VERSION 5.7 ;
  NOWIREEXTENSIONATPIN ON ;
  DIVIDERCHAR "/" ;
  BUSBITCHARS "[]" ;
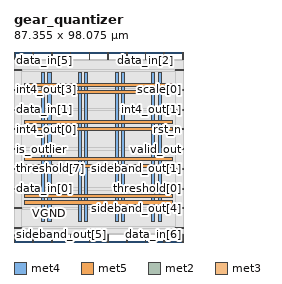
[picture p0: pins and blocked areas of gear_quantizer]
MACRO gear_quantizer
  CLASS BLOCK ;
  FOREIGN gear_quantizer ;
  ORIGIN 0.000 0.000 ;
  SIZE 87.355 BY 98.075 ;
  PIN VGND
    DIRECTION INOUT ;
    USE GROUND ;
    PORT
      LAYER met4 ;
        RECT 17.505 10.640 19.105 87.280 ;
    END
    PORT
      LAYER met4 ;
        RECT 36.480 10.640 38.080 87.280 ;
    END
    PORT
      LAYER met4 ;
        RECT 55.455 10.640 57.055 87.280 ;
    END
    PORT
      LAYER met4 ;
        RECT 74.430 10.640 76.030 87.280 ;
    END
    PORT
      LAYER met5 ;
        RECT 5.280 22.900 81.660 24.500 ;
    END
    PORT
      LAYER met5 ;
        RECT 5.280 41.940 81.660 43.540 ;
    END
    PORT
      LAYER met5 ;
        RECT 5.280 60.980 81.660 62.580 ;
    END
    PORT
      LAYER met5 ;
        RECT 5.280 80.020 81.660 81.620 ;
    END
  END VGND
  PIN VPWR
    DIRECTION INOUT ;
    USE POWER ;
    PORT
      LAYER met4 ;
        RECT 14.205 10.640 15.805 87.280 ;
    END
    PORT
      LAYER met4 ;
        RECT 33.180 10.640 34.780 87.280 ;
    END
    PORT
      LAYER met4 ;
        RECT 52.155 10.640 53.755 87.280 ;
    END
    PORT
      LAYER met4 ;
        RECT 71.130 10.640 72.730 87.280 ;
    END
    PORT
      LAYER met5 ;
        RECT 5.280 19.600 81.660 21.200 ;
    END
    PORT
      LAYER met5 ;
        RECT 5.280 38.640 81.660 40.240 ;
    END
    PORT
      LAYER met5 ;
        RECT 5.280 57.680 81.660 59.280 ;
    END
    PORT
      LAYER met5 ;
        RECT 5.280 76.720 81.660 78.320 ;
    END
  END VPWR
  PIN clk
    DIRECTION INPUT ;
    USE SIGNAL ;
    ANTENNAGATEAREA 0.852000 ;
    PORT
      LAYER met2 ;
        RECT 48.390 0.000 48.670 4.000 ;
    END
  END clk
  PIN data_in[0]
    DIRECTION INPUT ;
    USE SIGNAL ;
    ANTENNAGATEAREA 0.213000 ;
    PORT
      LAYER met3 ;
        RECT 0.000 27.240 4.000 27.840 ;
    END
  END data_in[0]
  PIN data_in[1]
    DIRECTION INPUT ;
    USE SIGNAL ;
    ANTENNAGATEAREA 0.196500 ;
    PORT
      LAYER met3 ;
        RECT 0.000 68.040 4.000 68.640 ;
    END
  END data_in[1]
  PIN data_in[2]
    DIRECTION INPUT ;
    USE SIGNAL ;
    ANTENNAGATEAREA 0.196500 ;
    PORT
      LAYER met2 ;
        RECT 67.710 94.075 67.990 98.075 ;
    END
  END data_in[2]
  PIN data_in[3]
    DIRECTION INPUT ;
    USE SIGNAL ;
    ANTENNAGATEAREA 0.213000 ;
    PORT
      LAYER met2 ;
        RECT 48.390 94.075 48.670 98.075 ;
    END
  END data_in[3]
  PIN data_in[4]
    DIRECTION INPUT ;
    USE SIGNAL ;
    ANTENNAGATEAREA 0.213000 ;
    PORT
      LAYER met2 ;
        RECT 58.050 94.075 58.330 98.075 ;
    END
  END data_in[4]
  PIN data_in[5]
    DIRECTION INPUT ;
    USE SIGNAL ;
    ANTENNAGATEAREA 0.159000 ;
    PORT
      LAYER met2 ;
        RECT 9.750 94.075 10.030 98.075 ;
    END
  END data_in[5]
  PIN data_in[6]
    DIRECTION INPUT ;
    USE SIGNAL ;
    ANTENNAGATEAREA 0.213000 ;
    PORT
      LAYER met2 ;
        RECT 87.030 0.000 87.310 4.000 ;
    END
  END data_in[6]
  PIN data_in[7]
    DIRECTION INPUT ;
    USE SIGNAL ;
    ANTENNAGATEAREA 0.213000 ;
    PORT
      LAYER met2 ;
        RECT 77.370 0.000 77.650 4.000 ;
    END
  END data_in[7]
  PIN int4_out[0]
    DIRECTION OUTPUT TRISTATE ;
    USE SIGNAL ;
    ANTENNADIFFAREA 0.795200 ;
    PORT
      LAYER met3 ;
        RECT 0.000 57.840 4.000 58.440 ;
    END
  END int4_out[0]
  PIN int4_out[1]
    DIRECTION OUTPUT TRISTATE ;
    USE SIGNAL ;
    ANTENNADIFFAREA 0.795200 ;
    PORT
      LAYER met3 ;
        RECT 83.355 68.040 87.355 68.640 ;
    END
  END int4_out[1]
  PIN int4_out[2]
    DIRECTION OUTPUT TRISTATE ;
    USE SIGNAL ;
    ANTENNADIFFAREA 0.795200 ;
    PORT
      LAYER met2 ;
        RECT 19.410 94.075 19.690 98.075 ;
    END
  END int4_out[2]
  PIN int4_out[3]
    DIRECTION OUTPUT TRISTATE ;
    USE SIGNAL ;
    ANTENNADIFFAREA 0.795200 ;
    PORT
      LAYER met3 ;
        RECT 0.000 78.240 4.000 78.840 ;
    END
  END int4_out[3]
  PIN is_outlier
    DIRECTION OUTPUT TRISTATE ;
    USE SIGNAL ;
    ANTENNADIFFAREA 0.795200 ;
    PORT
      LAYER met3 ;
        RECT 0.000 47.640 4.000 48.240 ;
    END
  END is_outlier
  PIN round_mode
    DIRECTION INPUT ;
    USE SIGNAL ;
    PORT
      LAYER met3 ;
        RECT 83.355 6.840 87.355 7.440 ;
    END
  END round_mode
  PIN rst_n
    DIRECTION INPUT ;
    USE SIGNAL ;
    ANTENNAGATEAREA 0.213000 ;
    PORT
      LAYER met3 ;
        RECT 83.355 57.840 87.355 58.440 ;
    END
  END rst_n
  PIN scale[0]
    DIRECTION INPUT ;
    USE SIGNAL ;
    ANTENNAGATEAREA 0.213000 ;
    PORT
      LAYER met3 ;
        RECT 83.355 78.240 87.355 78.840 ;
    END
  END scale[0]
  PIN scale[1]
    DIRECTION INPUT ;
    USE SIGNAL ;
    ANTENNAGATEAREA 0.126000 ;
    PORT
      LAYER met2 ;
        RECT 0.090 0.000 0.370 4.000 ;
    END
  END scale[1]
  PIN scale[2]
    DIRECTION INPUT ;
    USE SIGNAL ;
    ANTENNAGATEAREA 0.213000 ;
    PORT
      LAYER met2 ;
        RECT 0.090 94.075 0.370 98.075 ;
    END
  END scale[2]
  PIN scale[3]
    DIRECTION INPUT ;
    USE SIGNAL ;
    ANTENNAGATEAREA 0.213000 ;
    PORT
      LAYER met3 ;
        RECT 0.000 6.840 4.000 7.440 ;
    END
  END scale[3]
  PIN sideband_out[0]
    DIRECTION OUTPUT TRISTATE ;
    USE SIGNAL ;
    ANTENNADIFFAREA 0.795200 ;
    PORT
      LAYER met2 ;
        RECT 29.070 0.000 29.350 4.000 ;
    END
  END sideband_out[0]
  PIN sideband_out[1]
    DIRECTION OUTPUT TRISTATE ;
    USE SIGNAL ;
    ANTENNADIFFAREA 0.445500 ;
    PORT
      LAYER met3 ;
        RECT 83.355 37.440 87.355 38.040 ;
    END
  END sideband_out[1]
  PIN sideband_out[2]
    DIRECTION OUTPUT TRISTATE ;
    USE SIGNAL ;
    ANTENNADIFFAREA 0.795200 ;
    PORT
      LAYER met2 ;
        RECT 67.710 0.000 67.990 4.000 ;
    END
  END sideband_out[2]
  PIN sideband_out[3]
    DIRECTION OUTPUT TRISTATE ;
    USE SIGNAL ;
    ANTENNADIFFAREA 0.445500 ;
    PORT
      LAYER met2 ;
        RECT 77.370 94.075 77.650 98.075 ;
    END
  END sideband_out[3]
  PIN sideband_out[4]
    DIRECTION OUTPUT TRISTATE ;
    USE SIGNAL ;
    ANTENNADIFFAREA 0.445500 ;
    PORT
      LAYER met3 ;
        RECT 83.355 17.040 87.355 17.640 ;
    END
  END sideband_out[4]
  PIN sideband_out[5]
    DIRECTION OUTPUT TRISTATE ;
    USE SIGNAL ;
    ANTENNADIFFAREA 0.795200 ;
    PORT
      LAYER met2 ;
        RECT 9.750 0.000 10.030 4.000 ;
    END
  END sideband_out[5]
  PIN sideband_out[6]
    DIRECTION OUTPUT TRISTATE ;
    USE SIGNAL ;
    ANTENNADIFFAREA 0.795200 ;
    PORT
      LAYER met2 ;
        RECT 19.410 0.000 19.690 4.000 ;
    END
  END sideband_out[6]
  PIN sideband_out[7]
    DIRECTION OUTPUT TRISTATE ;
    USE SIGNAL ;
    ANTENNADIFFAREA 0.795200 ;
    PORT
      LAYER met3 ;
        RECT 0.000 17.040 4.000 17.640 ;
    END
  END sideband_out[7]
  PIN threshold[0]
    DIRECTION INPUT ;
    USE SIGNAL ;
    ANTENNAGATEAREA 0.196500 ;
    PORT
      LAYER met3 ;
        RECT 83.355 27.240 87.355 27.840 ;
    END
  END threshold[0]
  PIN threshold[1]
    DIRECTION INPUT ;
    USE SIGNAL ;
    ANTENNAGATEAREA 0.196500 ;
    PORT
      LAYER met2 ;
        RECT 38.730 0.000 39.010 4.000 ;
    END
  END threshold[1]
  PIN threshold[2]
    DIRECTION INPUT ;
    USE SIGNAL ;
    ANTENNAGATEAREA 0.196500 ;
    PORT
      LAYER met3 ;
        RECT 83.355 88.440 87.355 89.040 ;
    END
  END threshold[2]
  PIN threshold[3]
    DIRECTION INPUT ;
    USE SIGNAL ;
    ANTENNAGATEAREA 0.196500 ;
    PORT
      LAYER met2 ;
        RECT 87.030 94.075 87.310 98.075 ;
    END
  END threshold[3]
  PIN threshold[4]
    DIRECTION INPUT ;
    USE SIGNAL ;
    ANTENNAGATEAREA 0.196500 ;
    PORT
      LAYER met2 ;
        RECT 29.070 94.075 29.350 98.075 ;
    END
  END threshold[4]
  PIN threshold[5]
    DIRECTION INPUT ;
    USE SIGNAL ;
    ANTENNAGATEAREA 0.196500 ;
    PORT
      LAYER met2 ;
        RECT 38.730 94.075 39.010 98.075 ;
    END
  END threshold[5]
  PIN threshold[6]
    DIRECTION INPUT ;
    USE SIGNAL ;
    ANTENNAGATEAREA 0.196500 ;
    PORT
      LAYER met2 ;
        RECT 58.050 0.000 58.330 4.000 ;
    END
  END threshold[6]
  PIN threshold[7]
    DIRECTION INPUT ;
    USE SIGNAL ;
    ANTENNAGATEAREA 0.126000 ;
    PORT
      LAYER met3 ;
        RECT 0.000 37.440 4.000 38.040 ;
    END
  END threshold[7]
  PIN valid_in
    DIRECTION INPUT ;
    USE SIGNAL ;
    ANTENNAGATEAREA 0.196500 ;
    PORT
      LAYER met3 ;
        RECT 0.000 88.440 4.000 89.040 ;
    END
  END valid_in
  PIN valid_out
    DIRECTION OUTPUT TRISTATE ;
    USE SIGNAL ;
    ANTENNADIFFAREA 0.795200 ;
    PORT
      LAYER met3 ;
        RECT 83.355 47.640 87.355 48.240 ;
    END
  END valid_out
  OBS
      LAYER li1 ;
        RECT 5.520 10.795 81.420 87.125 ;
      LAYER met1 ;
        RECT 0.070 10.640 87.330 87.280 ;
      LAYER met2 ;
        RECT 0.650 93.795 9.470 94.075 ;
        RECT 10.310 93.795 19.130 94.075 ;
        RECT 19.970 93.795 28.790 94.075 ;
        RECT 29.630 93.795 38.450 94.075 ;
        RECT 39.290 93.795 48.110 94.075 ;
        RECT 48.950 93.795 57.770 94.075 ;
        RECT 58.610 93.795 67.430 94.075 ;
        RECT 68.270 93.795 77.090 94.075 ;
        RECT 77.930 93.795 86.750 94.075 ;
        RECT 0.100 4.280 87.300 93.795 ;
        RECT 0.650 4.000 9.470 4.280 ;
        RECT 10.310 4.000 19.130 4.280 ;
        RECT 19.970 4.000 28.790 4.280 ;
        RECT 29.630 4.000 38.450 4.280 ;
        RECT 39.290 4.000 48.110 4.280 ;
        RECT 48.950 4.000 57.770 4.280 ;
        RECT 58.610 4.000 67.430 4.280 ;
        RECT 68.270 4.000 77.090 4.280 ;
        RECT 77.930 4.000 86.750 4.280 ;
      LAYER met3 ;
        RECT 4.400 88.040 82.955 88.905 ;
        RECT 4.000 79.240 83.355 88.040 ;
        RECT 4.400 77.840 82.955 79.240 ;
        RECT 4.000 69.040 83.355 77.840 ;
        RECT 4.400 67.640 82.955 69.040 ;
        RECT 4.000 58.840 83.355 67.640 ;
        RECT 4.400 57.440 82.955 58.840 ;
        RECT 4.000 48.640 83.355 57.440 ;
        RECT 4.400 47.240 82.955 48.640 ;
        RECT 4.000 38.440 83.355 47.240 ;
        RECT 4.400 37.040 82.955 38.440 ;
        RECT 4.000 28.240 83.355 37.040 ;
        RECT 4.400 26.840 82.955 28.240 ;
        RECT 4.000 18.040 83.355 26.840 ;
        RECT 4.400 16.640 82.955 18.040 ;
        RECT 4.000 7.840 83.355 16.640 ;
        RECT 4.400 6.990 82.955 7.840 ;
  END
END gear_quantizer
END LIBRARY

